VERSION 5.7 ;
  NOWIREEXTENSIONATPIN ON ;
  DIVIDERCHAR "/" ;
  BUSBITCHARS "[]" ;
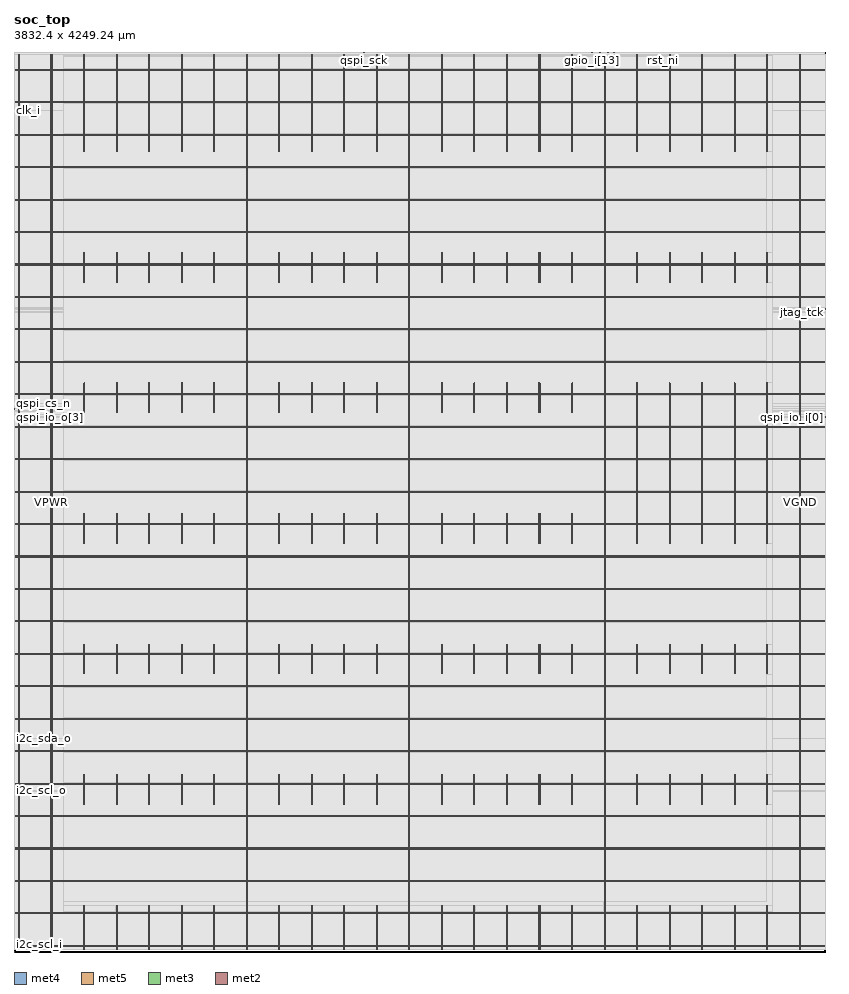
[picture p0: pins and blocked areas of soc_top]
MACRO soc_top
  CLASS BLOCK ;
  FOREIGN soc_top ;
  ORIGIN 0.000 0.000 ;
  SIZE 3832.400 BY 4249.240 ;
  PIN VGND
    DIRECTION INOUT ;
    USE GROUND ;
    PORT
      LAYER met4 ;
        RECT 24.340 10.640 25.940 4238.000 ;
    END
    PORT
      LAYER met4 ;
        RECT 177.940 10.640 179.540 4238.000 ;
    END
    PORT
      LAYER met4 ;
        RECT 331.540 10.640 333.140 220.320 ;
    END
    PORT
      LAYER met4 ;
        RECT 331.540 696.220 333.140 836.860 ;
    END
    PORT
      LAYER met4 ;
        RECT 331.540 1312.760 333.140 1453.400 ;
    END
    PORT
      LAYER met4 ;
        RECT 331.540 1929.300 333.140 2069.940 ;
    END
    PORT
      LAYER met4 ;
        RECT 331.540 2545.840 333.140 2686.480 ;
    END
    PORT
      LAYER met4 ;
        RECT 331.540 3162.380 333.140 3303.020 ;
    END
    PORT
      LAYER met4 ;
        RECT 331.540 3778.920 333.140 4238.000 ;
    END
    PORT
      LAYER met4 ;
        RECT 485.140 10.640 486.740 220.320 ;
    END
    PORT
      LAYER met4 ;
        RECT 485.140 696.220 486.740 836.860 ;
    END
    PORT
      LAYER met4 ;
        RECT 485.140 1312.760 486.740 1453.400 ;
    END
    PORT
      LAYER met4 ;
        RECT 485.140 1929.300 486.740 2069.940 ;
    END
    PORT
      LAYER met4 ;
        RECT 485.140 2545.840 486.740 2686.480 ;
    END
    PORT
      LAYER met4 ;
        RECT 485.140 3162.380 486.740 3303.020 ;
    END
    PORT
      LAYER met4 ;
        RECT 485.140 3778.920 486.740 4238.000 ;
    END
    PORT
      LAYER met4 ;
        RECT 638.740 10.640 640.340 220.320 ;
    END
    PORT
      LAYER met4 ;
        RECT 638.740 696.220 640.340 836.860 ;
    END
    PORT
      LAYER met4 ;
        RECT 638.740 1312.760 640.340 1453.400 ;
    END
    PORT
      LAYER met4 ;
        RECT 638.740 1929.300 640.340 2069.940 ;
    END
    PORT
      LAYER met4 ;
        RECT 638.740 2545.840 640.340 2686.480 ;
    END
    PORT
      LAYER met4 ;
        RECT 638.740 3162.380 640.340 3303.020 ;
    END
    PORT
      LAYER met4 ;
        RECT 638.740 3778.920 640.340 4238.000 ;
    END
    PORT
      LAYER met4 ;
        RECT 792.340 10.640 793.940 220.320 ;
    END
    PORT
      LAYER met4 ;
        RECT 792.340 696.220 793.940 836.860 ;
    END
    PORT
      LAYER met4 ;
        RECT 792.340 1312.760 793.940 1453.400 ;
    END
    PORT
      LAYER met4 ;
        RECT 792.340 1929.300 793.940 2069.940 ;
    END
    PORT
      LAYER met4 ;
        RECT 792.340 2545.840 793.940 2686.480 ;
    END
    PORT
      LAYER met4 ;
        RECT 792.340 3162.380 793.940 3303.020 ;
    END
    PORT
      LAYER met4 ;
        RECT 792.340 3778.920 793.940 4238.000 ;
    END
    PORT
      LAYER met4 ;
        RECT 945.940 10.640 947.540 220.320 ;
    END
    PORT
      LAYER met4 ;
        RECT 945.940 696.220 947.540 836.860 ;
    END
    PORT
      LAYER met4 ;
        RECT 945.940 1312.760 947.540 1453.400 ;
    END
    PORT
      LAYER met4 ;
        RECT 945.940 1929.300 947.540 2069.940 ;
    END
    PORT
      LAYER met4 ;
        RECT 945.940 2545.840 947.540 2686.480 ;
    END
    PORT
      LAYER met4 ;
        RECT 945.940 3162.380 947.540 3303.020 ;
    END
    PORT
      LAYER met4 ;
        RECT 945.940 3778.920 947.540 4238.000 ;
    END
    PORT
      LAYER met4 ;
        RECT 1099.540 10.640 1101.140 4238.000 ;
    END
    PORT
      LAYER met4 ;
        RECT 1253.140 10.640 1254.740 219.400 ;
    END
    PORT
      LAYER met4 ;
        RECT 1253.140 696.220 1254.740 835.940 ;
    END
    PORT
      LAYER met4 ;
        RECT 1253.140 1312.760 1254.740 1452.720 ;
    END
    PORT
      LAYER met4 ;
        RECT 1253.140 1929.300 1254.740 2069.020 ;
    END
    PORT
      LAYER met4 ;
        RECT 1253.140 2545.840 1254.740 2685.560 ;
    END
    PORT
      LAYER met4 ;
        RECT 1253.140 3162.380 1254.740 3302.320 ;
    END
    PORT
      LAYER met4 ;
        RECT 1253.140 3778.920 1254.740 4238.000 ;
    END
    PORT
      LAYER met4 ;
        RECT 1406.740 10.640 1408.340 220.320 ;
    END
    PORT
      LAYER met4 ;
        RECT 1406.740 696.220 1408.340 836.860 ;
    END
    PORT
      LAYER met4 ;
        RECT 1406.740 1312.760 1408.340 1453.400 ;
    END
    PORT
      LAYER met4 ;
        RECT 1406.740 1929.300 1408.340 2069.940 ;
    END
    PORT
      LAYER met4 ;
        RECT 1406.740 2545.840 1408.340 2686.480 ;
    END
    PORT
      LAYER met4 ;
        RECT 1406.740 3162.380 1408.340 3303.020 ;
    END
    PORT
      LAYER met4 ;
        RECT 1406.740 3778.920 1408.340 4238.000 ;
    END
    PORT
      LAYER met4 ;
        RECT 1560.340 10.640 1561.940 220.320 ;
    END
    PORT
      LAYER met4 ;
        RECT 1560.340 696.220 1561.940 836.860 ;
    END
    PORT
      LAYER met4 ;
        RECT 1560.340 1312.760 1561.940 1453.400 ;
    END
    PORT
      LAYER met4 ;
        RECT 1560.340 1929.300 1561.940 2069.940 ;
    END
    PORT
      LAYER met4 ;
        RECT 1560.340 2545.840 1561.940 2686.480 ;
    END
    PORT
      LAYER met4 ;
        RECT 1560.340 3162.380 1561.940 3303.020 ;
    END
    PORT
      LAYER met4 ;
        RECT 1560.340 3778.920 1561.940 4238.000 ;
    END
    PORT
      LAYER met4 ;
        RECT 1713.940 10.640 1715.540 220.320 ;
    END
    PORT
      LAYER met4 ;
        RECT 1713.940 696.220 1715.540 836.860 ;
    END
    PORT
      LAYER met4 ;
        RECT 1713.940 1312.760 1715.540 1453.400 ;
    END
    PORT
      LAYER met4 ;
        RECT 1713.940 1929.300 1715.540 2069.940 ;
    END
    PORT
      LAYER met4 ;
        RECT 1713.940 2545.840 1715.540 2686.480 ;
    END
    PORT
      LAYER met4 ;
        RECT 1713.940 3162.380 1715.540 3303.020 ;
    END
    PORT
      LAYER met4 ;
        RECT 1713.940 3778.920 1715.540 4238.000 ;
    END
    PORT
      LAYER met4 ;
        RECT 1867.540 10.640 1869.140 4238.000 ;
    END
    PORT
      LAYER met4 ;
        RECT 2021.140 10.640 2022.740 220.320 ;
    END
    PORT
      LAYER met4 ;
        RECT 2021.140 696.220 2022.740 836.860 ;
    END
    PORT
      LAYER met4 ;
        RECT 2021.140 1312.760 2022.740 1453.400 ;
    END
    PORT
      LAYER met4 ;
        RECT 2021.140 1929.300 2022.740 2069.940 ;
    END
    PORT
      LAYER met4 ;
        RECT 2021.140 2545.840 2022.740 2686.480 ;
    END
    PORT
      LAYER met4 ;
        RECT 2021.140 3162.380 2022.740 3303.020 ;
    END
    PORT
      LAYER met4 ;
        RECT 2021.140 3778.920 2022.740 4238.000 ;
    END
    PORT
      LAYER met4 ;
        RECT 2174.740 10.640 2176.340 220.320 ;
    END
    PORT
      LAYER met4 ;
        RECT 2174.740 696.220 2176.340 836.860 ;
    END
    PORT
      LAYER met4 ;
        RECT 2174.740 1312.760 2176.340 1453.400 ;
    END
    PORT
      LAYER met4 ;
        RECT 2174.740 1929.300 2176.340 2069.940 ;
    END
    PORT
      LAYER met4 ;
        RECT 2174.740 2545.840 2176.340 2686.480 ;
    END
    PORT
      LAYER met4 ;
        RECT 2174.740 3162.380 2176.340 3303.020 ;
    END
    PORT
      LAYER met4 ;
        RECT 2174.740 3778.920 2176.340 4238.000 ;
    END
    PORT
      LAYER met4 ;
        RECT 2328.340 10.640 2329.940 220.320 ;
    END
    PORT
      LAYER met4 ;
        RECT 2328.340 696.220 2329.940 836.860 ;
    END
    PORT
      LAYER met4 ;
        RECT 2328.340 1312.760 2329.940 1453.400 ;
    END
    PORT
      LAYER met4 ;
        RECT 2328.340 1929.300 2329.940 2069.940 ;
    END
    PORT
      LAYER met4 ;
        RECT 2328.340 2545.840 2329.940 2686.480 ;
    END
    PORT
      LAYER met4 ;
        RECT 2328.340 3162.380 2329.940 3303.020 ;
    END
    PORT
      LAYER met4 ;
        RECT 2328.340 3778.920 2329.940 4238.000 ;
    END
    PORT
      LAYER met4 ;
        RECT 2481.940 10.640 2483.540 219.400 ;
    END
    PORT
      LAYER met4 ;
        RECT 2481.940 697.140 2483.540 835.940 ;
    END
    PORT
      LAYER met4 ;
        RECT 2481.940 1313.680 2483.540 1452.720 ;
    END
    PORT
      LAYER met4 ;
        RECT 2481.940 1930.220 2483.540 2069.020 ;
    END
    PORT
      LAYER met4 ;
        RECT 2481.940 2546.760 2483.540 2685.560 ;
    END
    PORT
      LAYER met4 ;
        RECT 2481.940 3163.300 2483.540 3302.320 ;
    END
    PORT
      LAYER met4 ;
        RECT 2481.940 3779.840 2483.540 4238.000 ;
    END
    PORT
      LAYER met4 ;
        RECT 2635.540 10.640 2637.140 220.320 ;
    END
    PORT
      LAYER met4 ;
        RECT 2635.540 696.220 2637.140 836.860 ;
    END
    PORT
      LAYER met4 ;
        RECT 2635.540 1312.760 2637.140 1453.400 ;
    END
    PORT
      LAYER met4 ;
        RECT 2635.540 1929.300 2637.140 2069.940 ;
    END
    PORT
      LAYER met4 ;
        RECT 2635.540 2545.840 2637.140 2686.480 ;
    END
    PORT
      LAYER met4 ;
        RECT 2635.540 3162.380 2637.140 3303.020 ;
    END
    PORT
      LAYER met4 ;
        RECT 2635.540 3778.920 2637.140 4238.000 ;
    END
    PORT
      LAYER met4 ;
        RECT 2789.140 10.640 2790.740 4238.000 ;
    END
    PORT
      LAYER met4 ;
        RECT 2942.740 10.640 2944.340 220.320 ;
    END
    PORT
      LAYER met4 ;
        RECT 2942.740 696.220 2944.340 836.860 ;
    END
    PORT
      LAYER met4 ;
        RECT 2942.740 1312.760 2944.340 1453.400 ;
    END
    PORT
      LAYER met4 ;
        RECT 2942.740 1929.300 2944.340 2686.480 ;
    END
    PORT
      LAYER met4 ;
        RECT 2942.740 3162.380 2944.340 3303.020 ;
    END
    PORT
      LAYER met4 ;
        RECT 2942.740 3778.920 2944.340 4238.000 ;
    END
    PORT
      LAYER met4 ;
        RECT 3096.340 10.640 3097.940 219.400 ;
    END
    PORT
      LAYER met4 ;
        RECT 3096.340 696.220 3097.940 835.940 ;
    END
    PORT
      LAYER met4 ;
        RECT 3096.340 1312.760 3097.940 1452.720 ;
    END
    PORT
      LAYER met4 ;
        RECT 3096.340 1929.300 3097.940 2685.560 ;
    END
    PORT
      LAYER met4 ;
        RECT 3096.340 3162.380 3097.940 3302.320 ;
    END
    PORT
      LAYER met4 ;
        RECT 3096.340 3778.920 3097.940 4238.000 ;
    END
    PORT
      LAYER met4 ;
        RECT 3249.940 10.640 3251.540 220.320 ;
    END
    PORT
      LAYER met4 ;
        RECT 3249.940 696.220 3251.540 836.860 ;
    END
    PORT
      LAYER met4 ;
        RECT 3249.940 1312.760 3251.540 1453.400 ;
    END
    PORT
      LAYER met4 ;
        RECT 3249.940 1929.300 3251.540 2686.480 ;
    END
    PORT
      LAYER met4 ;
        RECT 3249.940 3162.380 3251.540 3303.020 ;
    END
    PORT
      LAYER met4 ;
        RECT 3249.940 3778.920 3251.540 4238.000 ;
    END
    PORT
      LAYER met4 ;
        RECT 3403.540 10.640 3405.140 219.400 ;
    END
    PORT
      LAYER met4 ;
        RECT 3403.540 697.140 3405.140 835.940 ;
    END
    PORT
      LAYER met4 ;
        RECT 3403.540 1313.680 3405.140 1452.720 ;
    END
    PORT
      LAYER met4 ;
        RECT 3403.540 1930.220 3405.140 2685.560 ;
    END
    PORT
      LAYER met4 ;
        RECT 3403.540 3163.300 3405.140 3302.320 ;
    END
    PORT
      LAYER met4 ;
        RECT 3403.540 3779.840 3405.140 4238.000 ;
    END
    PORT
      LAYER met4 ;
        RECT 3557.140 10.640 3558.740 220.320 ;
    END
    PORT
      LAYER met4 ;
        RECT 3557.140 696.220 3558.740 836.860 ;
    END
    PORT
      LAYER met4 ;
        RECT 3557.140 1312.760 3558.740 1453.400 ;
    END
    PORT
      LAYER met4 ;
        RECT 3557.140 1929.300 3558.740 2686.480 ;
    END
    PORT
      LAYER met4 ;
        RECT 3557.140 3162.380 3558.740 3303.020 ;
    END
    PORT
      LAYER met4 ;
        RECT 3557.140 3778.920 3558.740 4238.000 ;
    END
    PORT
      LAYER met4 ;
        RECT 3710.740 10.640 3712.340 4238.000 ;
    END
    PORT
      LAYER met5 ;
        RECT 5.520 30.030 3826.740 31.630 ;
    END
    PORT
      LAYER met5 ;
        RECT 5.520 183.210 3826.740 184.810 ;
    END
    PORT
      LAYER met5 ;
        RECT 5.520 336.390 3826.740 337.990 ;
    END
    PORT
      LAYER met5 ;
        RECT 5.520 489.570 3826.740 491.170 ;
    END
    PORT
      LAYER met5 ;
        RECT 5.520 642.750 3826.740 644.350 ;
    END
    PORT
      LAYER met5 ;
        RECT 5.520 795.930 3826.740 797.530 ;
    END
    PORT
      LAYER met5 ;
        RECT 5.520 949.110 3826.740 950.710 ;
    END
    PORT
      LAYER met5 ;
        RECT 5.520 1102.290 3826.740 1103.890 ;
    END
    PORT
      LAYER met5 ;
        RECT 5.520 1255.470 3826.740 1257.070 ;
    END
    PORT
      LAYER met5 ;
        RECT 5.520 1408.650 3826.740 1410.250 ;
    END
    PORT
      LAYER met5 ;
        RECT 5.520 1561.830 3826.740 1563.430 ;
    END
    PORT
      LAYER met5 ;
        RECT 5.520 1715.010 3826.740 1716.610 ;
    END
    PORT
      LAYER met5 ;
        RECT 5.520 1868.190 3826.740 1869.790 ;
    END
    PORT
      LAYER met5 ;
        RECT 5.520 2021.370 3826.740 2022.970 ;
    END
    PORT
      LAYER met5 ;
        RECT 5.520 2174.550 3826.740 2176.150 ;
    END
    PORT
      LAYER met5 ;
        RECT 5.520 2327.730 3826.740 2329.330 ;
    END
    PORT
      LAYER met5 ;
        RECT 5.520 2480.910 3826.740 2482.510 ;
    END
    PORT
      LAYER met5 ;
        RECT 5.520 2634.090 3826.740 2635.690 ;
    END
    PORT
      LAYER met5 ;
        RECT 5.520 2787.270 3826.740 2788.870 ;
    END
    PORT
      LAYER met5 ;
        RECT 5.520 2940.450 3826.740 2942.050 ;
    END
    PORT
      LAYER met5 ;
        RECT 5.520 3093.630 3826.740 3095.230 ;
    END
    PORT
      LAYER met5 ;
        RECT 5.520 3246.810 3826.740 3248.410 ;
    END
    PORT
      LAYER met5 ;
        RECT 5.520 3399.990 3826.740 3401.590 ;
    END
    PORT
      LAYER met5 ;
        RECT 5.520 3553.170 3826.740 3554.770 ;
    END
    PORT
      LAYER met5 ;
        RECT 5.520 3706.350 3826.740 3707.950 ;
    END
    PORT
      LAYER met5 ;
        RECT 5.520 3859.530 3826.740 3861.130 ;
    END
    PORT
      LAYER met5 ;
        RECT 5.520 4012.710 3826.740 4014.310 ;
    END
    PORT
      LAYER met5 ;
        RECT 5.520 4165.890 3826.740 4167.490 ;
    END
  END VGND
  PIN VPWR
    DIRECTION INOUT ;
    USE POWER ;
    PORT
      LAYER met4 ;
        RECT 21.040 10.640 22.640 4238.000 ;
    END
    PORT
      LAYER met4 ;
        RECT 174.640 10.640 176.240 4238.000 ;
    END
    PORT
      LAYER met4 ;
        RECT 328.240 10.640 329.840 219.400 ;
    END
    PORT
      LAYER met4 ;
        RECT 328.240 696.220 329.840 835.940 ;
    END
    PORT
      LAYER met4 ;
        RECT 328.240 1312.760 329.840 1452.480 ;
    END
    PORT
      LAYER met4 ;
        RECT 328.240 1929.300 329.840 2069.020 ;
    END
    PORT
      LAYER met4 ;
        RECT 328.240 2545.840 329.840 2685.560 ;
    END
    PORT
      LAYER met4 ;
        RECT 328.240 3162.380 329.840 3302.100 ;
    END
    PORT
      LAYER met4 ;
        RECT 328.240 3778.920 329.840 4238.000 ;
    END
    PORT
      LAYER met4 ;
        RECT 481.840 10.640 483.440 219.400 ;
    END
    PORT
      LAYER met4 ;
        RECT 481.840 696.220 483.440 835.940 ;
    END
    PORT
      LAYER met4 ;
        RECT 481.840 1312.760 483.440 1452.480 ;
    END
    PORT
      LAYER met4 ;
        RECT 481.840 1929.300 483.440 2069.020 ;
    END
    PORT
      LAYER met4 ;
        RECT 481.840 2545.840 483.440 2685.560 ;
    END
    PORT
      LAYER met4 ;
        RECT 481.840 3162.380 483.440 3302.100 ;
    END
    PORT
      LAYER met4 ;
        RECT 481.840 3778.920 483.440 4238.000 ;
    END
    PORT
      LAYER met4 ;
        RECT 635.440 10.640 637.040 220.320 ;
    END
    PORT
      LAYER met4 ;
        RECT 635.440 696.220 637.040 836.860 ;
    END
    PORT
      LAYER met4 ;
        RECT 635.440 1312.760 637.040 1453.400 ;
    END
    PORT
      LAYER met4 ;
        RECT 635.440 1929.300 637.040 2069.940 ;
    END
    PORT
      LAYER met4 ;
        RECT 635.440 2545.840 637.040 2686.480 ;
    END
    PORT
      LAYER met4 ;
        RECT 635.440 3162.380 637.040 3303.020 ;
    END
    PORT
      LAYER met4 ;
        RECT 635.440 3778.920 637.040 4238.000 ;
    END
    PORT
      LAYER met4 ;
        RECT 789.040 10.640 790.640 220.320 ;
    END
    PORT
      LAYER met4 ;
        RECT 789.040 696.220 790.640 836.860 ;
    END
    PORT
      LAYER met4 ;
        RECT 789.040 1312.760 790.640 1453.400 ;
    END
    PORT
      LAYER met4 ;
        RECT 789.040 1929.300 790.640 2069.940 ;
    END
    PORT
      LAYER met4 ;
        RECT 789.040 2545.840 790.640 2686.480 ;
    END
    PORT
      LAYER met4 ;
        RECT 789.040 3162.380 790.640 3303.020 ;
    END
    PORT
      LAYER met4 ;
        RECT 789.040 3778.920 790.640 4238.000 ;
    END
    PORT
      LAYER met4 ;
        RECT 942.640 10.640 944.240 220.320 ;
    END
    PORT
      LAYER met4 ;
        RECT 942.640 696.220 944.240 836.860 ;
    END
    PORT
      LAYER met4 ;
        RECT 942.640 1312.760 944.240 1453.400 ;
    END
    PORT
      LAYER met4 ;
        RECT 942.640 1929.300 944.240 2069.940 ;
    END
    PORT
      LAYER met4 ;
        RECT 942.640 2545.840 944.240 2686.480 ;
    END
    PORT
      LAYER met4 ;
        RECT 942.640 3162.380 944.240 3303.020 ;
    END
    PORT
      LAYER met4 ;
        RECT 942.640 3778.920 944.240 4238.000 ;
    END
    PORT
      LAYER met4 ;
        RECT 1096.240 10.640 1097.840 4238.000 ;
    END
    PORT
      LAYER met4 ;
        RECT 1249.840 10.640 1251.440 220.320 ;
    END
    PORT
      LAYER met4 ;
        RECT 1249.840 696.220 1251.440 836.860 ;
    END
    PORT
      LAYER met4 ;
        RECT 1249.840 1312.760 1251.440 1453.400 ;
    END
    PORT
      LAYER met4 ;
        RECT 1249.840 1929.300 1251.440 2069.940 ;
    END
    PORT
      LAYER met4 ;
        RECT 1249.840 2545.840 1251.440 2686.480 ;
    END
    PORT
      LAYER met4 ;
        RECT 1249.840 3162.380 1251.440 3303.020 ;
    END
    PORT
      LAYER met4 ;
        RECT 1249.840 3778.920 1251.440 4238.000 ;
    END
    PORT
      LAYER met4 ;
        RECT 1403.440 10.640 1405.040 219.400 ;
    END
    PORT
      LAYER met4 ;
        RECT 1403.440 696.220 1405.040 835.940 ;
    END
    PORT
      LAYER met4 ;
        RECT 1403.440 1312.760 1405.040 1452.480 ;
    END
    PORT
      LAYER met4 ;
        RECT 1403.440 1929.300 1405.040 2069.020 ;
    END
    PORT
      LAYER met4 ;
        RECT 1403.440 2545.840 1405.040 2685.560 ;
    END
    PORT
      LAYER met4 ;
        RECT 1403.440 3162.380 1405.040 3302.100 ;
    END
    PORT
      LAYER met4 ;
        RECT 1403.440 3778.920 1405.040 4238.000 ;
    END
    PORT
      LAYER met4 ;
        RECT 1557.040 10.640 1558.640 220.320 ;
    END
    PORT
      LAYER met4 ;
        RECT 1557.040 696.220 1558.640 836.860 ;
    END
    PORT
      LAYER met4 ;
        RECT 1557.040 1312.760 1558.640 1453.400 ;
    END
    PORT
      LAYER met4 ;
        RECT 1557.040 1929.300 1558.640 2069.940 ;
    END
    PORT
      LAYER met4 ;
        RECT 1557.040 2545.840 1558.640 2686.480 ;
    END
    PORT
      LAYER met4 ;
        RECT 1557.040 3162.380 1558.640 3303.020 ;
    END
    PORT
      LAYER met4 ;
        RECT 1557.040 3778.920 1558.640 4238.000 ;
    END
    PORT
      LAYER met4 ;
        RECT 1710.640 10.640 1712.240 220.320 ;
    END
    PORT
      LAYER met4 ;
        RECT 1710.640 696.220 1712.240 836.860 ;
    END
    PORT
      LAYER met4 ;
        RECT 1710.640 1312.760 1712.240 1453.400 ;
    END
    PORT
      LAYER met4 ;
        RECT 1710.640 1929.300 1712.240 2069.940 ;
    END
    PORT
      LAYER met4 ;
        RECT 1710.640 2545.840 1712.240 2686.480 ;
    END
    PORT
      LAYER met4 ;
        RECT 1710.640 3162.380 1712.240 3303.020 ;
    END
    PORT
      LAYER met4 ;
        RECT 1710.640 3778.920 1712.240 4238.000 ;
    END
    PORT
      LAYER met4 ;
        RECT 1864.240 10.640 1865.840 4238.000 ;
    END
    PORT
      LAYER met4 ;
        RECT 2017.840 10.640 2019.440 220.320 ;
    END
    PORT
      LAYER met4 ;
        RECT 2017.840 696.220 2019.440 836.860 ;
    END
    PORT
      LAYER met4 ;
        RECT 2017.840 1312.760 2019.440 1453.400 ;
    END
    PORT
      LAYER met4 ;
        RECT 2017.840 1929.300 2019.440 2069.940 ;
    END
    PORT
      LAYER met4 ;
        RECT 2017.840 2545.840 2019.440 2686.480 ;
    END
    PORT
      LAYER met4 ;
        RECT 2017.840 3162.380 2019.440 3303.020 ;
    END
    PORT
      LAYER met4 ;
        RECT 2017.840 3778.920 2019.440 4238.000 ;
    END
    PORT
      LAYER met4 ;
        RECT 2171.440 10.640 2173.040 219.400 ;
    END
    PORT
      LAYER met4 ;
        RECT 2171.440 697.140 2173.040 835.940 ;
    END
    PORT
      LAYER met4 ;
        RECT 2171.440 1313.520 2173.040 1452.480 ;
    END
    PORT
      LAYER met4 ;
        RECT 2171.440 1930.220 2173.040 2069.020 ;
    END
    PORT
      LAYER met4 ;
        RECT 2171.440 2546.760 2173.040 2685.560 ;
    END
    PORT
      LAYER met4 ;
        RECT 2171.440 3163.120 2173.040 3302.100 ;
    END
    PORT
      LAYER met4 ;
        RECT 2171.440 3779.840 2173.040 4238.000 ;
    END
    PORT
      LAYER met4 ;
        RECT 2325.040 10.640 2326.640 220.320 ;
    END
    PORT
      LAYER met4 ;
        RECT 2325.040 696.220 2326.640 836.860 ;
    END
    PORT
      LAYER met4 ;
        RECT 2325.040 1312.760 2326.640 1453.400 ;
    END
    PORT
      LAYER met4 ;
        RECT 2325.040 1929.300 2326.640 2069.940 ;
    END
    PORT
      LAYER met4 ;
        RECT 2325.040 2545.840 2326.640 2686.480 ;
    END
    PORT
      LAYER met4 ;
        RECT 2325.040 3162.380 2326.640 3303.020 ;
    END
    PORT
      LAYER met4 ;
        RECT 2325.040 3778.920 2326.640 4238.000 ;
    END
    PORT
      LAYER met4 ;
        RECT 2478.640 10.640 2480.240 220.320 ;
    END
    PORT
      LAYER met4 ;
        RECT 2478.640 696.220 2480.240 836.860 ;
    END
    PORT
      LAYER met4 ;
        RECT 2478.640 1312.760 2480.240 1453.400 ;
    END
    PORT
      LAYER met4 ;
        RECT 2478.640 1929.300 2480.240 2069.940 ;
    END
    PORT
      LAYER met4 ;
        RECT 2478.640 2545.840 2480.240 2686.480 ;
    END
    PORT
      LAYER met4 ;
        RECT 2478.640 3162.380 2480.240 3303.020 ;
    END
    PORT
      LAYER met4 ;
        RECT 2478.640 3778.920 2480.240 4238.000 ;
    END
    PORT
      LAYER met4 ;
        RECT 2632.240 10.640 2633.840 219.400 ;
    END
    PORT
      LAYER met4 ;
        RECT 2632.240 696.220 2633.840 835.940 ;
    END
    PORT
      LAYER met4 ;
        RECT 2632.240 1312.760 2633.840 1452.480 ;
    END
    PORT
      LAYER met4 ;
        RECT 2632.240 1929.300 2633.840 2069.020 ;
    END
    PORT
      LAYER met4 ;
        RECT 2632.240 2545.840 2633.840 2685.560 ;
    END
    PORT
      LAYER met4 ;
        RECT 2632.240 3162.380 2633.840 3302.100 ;
    END
    PORT
      LAYER met4 ;
        RECT 2632.240 3778.920 2633.840 4238.000 ;
    END
    PORT
      LAYER met4 ;
        RECT 2785.840 10.640 2787.440 4238.000 ;
    END
    PORT
      LAYER met4 ;
        RECT 2939.440 10.640 2941.040 220.320 ;
    END
    PORT
      LAYER met4 ;
        RECT 2939.440 696.220 2941.040 836.860 ;
    END
    PORT
      LAYER met4 ;
        RECT 2939.440 1312.760 2941.040 1453.400 ;
    END
    PORT
      LAYER met4 ;
        RECT 2939.440 1929.300 2941.040 2686.480 ;
    END
    PORT
      LAYER met4 ;
        RECT 2939.440 3162.380 2941.040 3303.020 ;
    END
    PORT
      LAYER met4 ;
        RECT 2939.440 3778.920 2941.040 4238.000 ;
    END
    PORT
      LAYER met4 ;
        RECT 3093.040 10.640 3094.640 220.320 ;
    END
    PORT
      LAYER met4 ;
        RECT 3093.040 696.220 3094.640 836.860 ;
    END
    PORT
      LAYER met4 ;
        RECT 3093.040 1312.760 3094.640 1453.400 ;
    END
    PORT
      LAYER met4 ;
        RECT 3093.040 1929.300 3094.640 2686.480 ;
    END
    PORT
      LAYER met4 ;
        RECT 3093.040 3162.380 3094.640 3303.020 ;
    END
    PORT
      LAYER met4 ;
        RECT 3093.040 3778.920 3094.640 4238.000 ;
    END
    PORT
      LAYER met4 ;
        RECT 3246.640 10.640 3248.240 220.320 ;
    END
    PORT
      LAYER met4 ;
        RECT 3246.640 696.220 3248.240 836.860 ;
    END
    PORT
      LAYER met4 ;
        RECT 3246.640 1312.760 3248.240 1453.400 ;
    END
    PORT
      LAYER met4 ;
        RECT 3246.640 1929.300 3248.240 2686.480 ;
    END
    PORT
      LAYER met4 ;
        RECT 3246.640 3162.380 3248.240 3303.020 ;
    END
    PORT
      LAYER met4 ;
        RECT 3246.640 3778.920 3248.240 4238.000 ;
    END
    PORT
      LAYER met4 ;
        RECT 3400.240 10.640 3401.840 220.320 ;
    END
    PORT
      LAYER met4 ;
        RECT 3400.240 696.220 3401.840 836.860 ;
    END
    PORT
      LAYER met4 ;
        RECT 3400.240 1312.760 3401.840 1453.400 ;
    END
    PORT
      LAYER met4 ;
        RECT 3400.240 1929.300 3401.840 2686.480 ;
    END
    PORT
      LAYER met4 ;
        RECT 3400.240 3162.380 3401.840 3303.020 ;
    END
    PORT
      LAYER met4 ;
        RECT 3400.240 3778.920 3401.840 4238.000 ;
    END
    PORT
      LAYER met4 ;
        RECT 3553.840 10.640 3555.440 220.320 ;
    END
    PORT
      LAYER met4 ;
        RECT 3553.840 697.140 3555.440 836.860 ;
    END
    PORT
      LAYER met4 ;
        RECT 3553.840 1313.520 3555.440 1453.400 ;
    END
    PORT
      LAYER met4 ;
        RECT 3553.840 1930.220 3555.440 2686.480 ;
    END
    PORT
      LAYER met4 ;
        RECT 3553.840 3163.120 3555.440 3303.020 ;
    END
    PORT
      LAYER met4 ;
        RECT 3553.840 3779.840 3555.440 4238.000 ;
    END
    PORT
      LAYER met4 ;
        RECT 3707.440 10.640 3709.040 4238.000 ;
    END
    PORT
      LAYER met5 ;
        RECT 5.520 26.730 3826.740 28.330 ;
    END
    PORT
      LAYER met5 ;
        RECT 5.520 179.910 3826.740 181.510 ;
    END
    PORT
      LAYER met5 ;
        RECT 5.520 333.090 3826.740 334.690 ;
    END
    PORT
      LAYER met5 ;
        RECT 5.520 486.270 3826.740 487.870 ;
    END
    PORT
      LAYER met5 ;
        RECT 5.520 639.450 3826.740 641.050 ;
    END
    PORT
      LAYER met5 ;
        RECT 5.520 792.630 3826.740 794.230 ;
    END
    PORT
      LAYER met5 ;
        RECT 5.520 945.810 3826.740 947.410 ;
    END
    PORT
      LAYER met5 ;
        RECT 5.520 1098.990 3826.740 1100.590 ;
    END
    PORT
      LAYER met5 ;
        RECT 5.520 1252.170 3826.740 1253.770 ;
    END
    PORT
      LAYER met5 ;
        RECT 5.520 1405.350 3826.740 1406.950 ;
    END
    PORT
      LAYER met5 ;
        RECT 5.520 1558.530 3826.740 1560.130 ;
    END
    PORT
      LAYER met5 ;
        RECT 5.520 1711.710 3826.740 1713.310 ;
    END
    PORT
      LAYER met5 ;
        RECT 5.520 1864.890 3826.740 1866.490 ;
    END
    PORT
      LAYER met5 ;
        RECT 5.520 2018.070 3826.740 2019.670 ;
    END
    PORT
      LAYER met5 ;
        RECT 5.520 2171.250 3826.740 2172.850 ;
    END
    PORT
      LAYER met5 ;
        RECT 5.520 2324.430 3826.740 2326.030 ;
    END
    PORT
      LAYER met5 ;
        RECT 5.520 2477.610 3826.740 2479.210 ;
    END
    PORT
      LAYER met5 ;
        RECT 5.520 2630.790 3826.740 2632.390 ;
    END
    PORT
      LAYER met5 ;
        RECT 5.520 2783.970 3826.740 2785.570 ;
    END
    PORT
      LAYER met5 ;
        RECT 5.520 2937.150 3826.740 2938.750 ;
    END
    PORT
      LAYER met5 ;
        RECT 5.520 3090.330 3826.740 3091.930 ;
    END
    PORT
      LAYER met5 ;
        RECT 5.520 3243.510 3826.740 3245.110 ;
    END
    PORT
      LAYER met5 ;
        RECT 5.520 3396.690 3826.740 3398.290 ;
    END
    PORT
      LAYER met5 ;
        RECT 5.520 3549.870 3826.740 3551.470 ;
    END
    PORT
      LAYER met5 ;
        RECT 5.520 3703.050 3826.740 3704.650 ;
    END
    PORT
      LAYER met5 ;
        RECT 5.520 3856.230 3826.740 3857.830 ;
    END
    PORT
      LAYER met5 ;
        RECT 5.520 4009.410 3826.740 4011.010 ;
    END
    PORT
      LAYER met5 ;
        RECT 5.520 4162.590 3826.740 4164.190 ;
    END
  END VPWR
  PIN clk_i
    DIRECTION INPUT ;
    USE SIGNAL ;
    ANTENNAGATEAREA 2.138700 ;
    ANTENNADIFFAREA 0.434700 ;
    PORT
      LAYER met3 ;
        RECT 0.000 3973.960 0.600 3974.560 ;
    END
  END clk_i
  PIN gpio_i[0]
    DIRECTION INPUT ;
    USE SIGNAL ;
    ANTENNAGATEAREA 0.213000 ;
    PORT
      LAYER met2 ;
        RECT 2809.770 4248.960 2810.050 4249.240 ;
    END
  END gpio_i[0]
  PIN gpio_i[10]
    DIRECTION INPUT ;
    USE SIGNAL ;
    ANTENNAGATEAREA 0.213000 ;
    PORT
      LAYER met2 ;
        RECT 2767.450 4248.960 2767.730 4249.240 ;
    END
  END gpio_i[10]
  PIN gpio_i[11]
    DIRECTION INPUT ;
    USE SIGNAL ;
    ANTENNAGATEAREA 0.213000 ;
    PORT
      LAYER met2 ;
        RECT 2729.730 4248.960 2730.010 4249.240 ;
    END
  END gpio_i[11]
  PIN gpio_i[12]
    DIRECTION INPUT ;
    USE SIGNAL ;
    ANTENNAGATEAREA 0.213000 ;
    PORT
      LAYER met2 ;
        RECT 2786.770 4248.960 2787.050 4249.240 ;
    END
  END gpio_i[12]
  PIN gpio_i[13]
    DIRECTION INPUT ;
    USE SIGNAL ;
    ANTENNAGATEAREA 0.213000 ;
    PORT
      LAYER met2 ;
        RECT 2730.650 4248.960 2730.930 4249.240 ;
    END
  END gpio_i[13]
  PIN gpio_i[14]
    DIRECTION INPUT ;
    USE SIGNAL ;
    ANTENNAGATEAREA 0.213000 ;
    PORT
      LAYER met2 ;
        RECT 2833.690 4248.960 2833.970 4249.240 ;
    END
  END gpio_i[14]
  PIN gpio_i[15]
    DIRECTION INPUT ;
    USE SIGNAL ;
    ANTENNAGATEAREA 0.213000 ;
    PORT
      LAYER met2 ;
        RECT 2841.970 4248.960 2842.250 4249.240 ;
    END
  END gpio_i[15]
  PIN gpio_i[1]
    DIRECTION INPUT ;
    USE SIGNAL ;
    ANTENNAGATEAREA 0.213000 ;
    PORT
      LAYER met2 ;
        RECT 2769.290 4248.960 2769.570 4249.240 ;
    END
  END gpio_i[1]
  PIN gpio_i[2]
    DIRECTION INPUT ;
    USE SIGNAL ;
    ANTENNAGATEAREA 0.213000 ;
    PORT
      LAYER met2 ;
        RECT 2726.970 4248.960 2727.250 4249.240 ;
    END
  END gpio_i[2]
  PIN gpio_i[3]
    DIRECTION INPUT ;
    USE SIGNAL ;
    ANTENNAGATEAREA 0.213000 ;
    PORT
      LAYER met2 ;
        RECT 2727.890 4248.960 2728.170 4249.240 ;
    END
  END gpio_i[3]
  PIN gpio_i[4]
    DIRECTION INPUT ;
    USE SIGNAL ;
    ANTENNAGATEAREA 0.213000 ;
    PORT
      LAYER met2 ;
        RECT 2728.810 4248.960 2729.090 4249.240 ;
    END
  END gpio_i[4]
  PIN gpio_i[5]
    DIRECTION INPUT ;
    USE SIGNAL ;
    ANTENNAGATEAREA 0.213000 ;
    PORT
      LAYER met2 ;
        RECT 2820.810 4248.960 2821.090 4249.240 ;
    END
  END gpio_i[5]
  PIN gpio_i[6]
    DIRECTION INPUT ;
    USE SIGNAL ;
    ANTENNAGATEAREA 0.213000 ;
    PORT
      LAYER met2 ;
        RECT 2832.770 4248.960 2833.050 4249.240 ;
    END
  END gpio_i[6]
  PIN gpio_i[7]
    DIRECTION INPUT ;
    USE SIGNAL ;
    ANTENNAGATEAREA 0.213000 ;
    PORT
      LAYER met2 ;
        RECT 2842.890 4248.960 2843.170 4249.240 ;
    END
  END gpio_i[7]
  PIN gpio_i[8]
    DIRECTION INPUT ;
    USE SIGNAL ;
    ANTENNAGATEAREA 0.213000 ;
    PORT
      LAYER met2 ;
        RECT 2828.170 4248.960 2828.450 4249.240 ;
    END
  END gpio_i[8]
  PIN gpio_i[9]
    DIRECTION INPUT ;
    USE SIGNAL ;
    ANTENNAGATEAREA 0.213000 ;
    PORT
      LAYER met2 ;
        RECT 2738.930 4248.960 2739.210 4249.240 ;
    END
  END gpio_i[9]
  PIN gpio_o[0]
    DIRECTION OUTPUT ;
    USE SIGNAL ;
    ANTENNADIFFAREA 0.702900 ;
    PORT
      LAYER met2 ;
        RECT 2802.410 4248.960 2802.690 4249.240 ;
    END
  END gpio_o[0]
  PIN gpio_o[10]
    DIRECTION OUTPUT ;
    USE SIGNAL ;
    ANTENNADIFFAREA 0.702900 ;
    PORT
      LAYER met2 ;
        RECT 2781.250 4248.960 2781.530 4249.240 ;
    END
  END gpio_o[10]
  PIN gpio_o[11]
    DIRECTION OUTPUT ;
    USE SIGNAL ;
    ANTENNADIFFAREA 0.702900 ;
    PORT
      LAYER met2 ;
        RECT 2741.690 4248.960 2741.970 4249.240 ;
    END
  END gpio_o[11]
  PIN gpio_o[12]
    DIRECTION OUTPUT ;
    USE SIGNAL ;
    ANTENNADIFFAREA 0.702900 ;
    PORT
      LAYER met2 ;
        RECT 2777.570 4248.960 2777.850 4249.240 ;
    END
  END gpio_o[12]
  PIN gpio_o[13]
    DIRECTION OUTPUT ;
    USE SIGNAL ;
    ANTENNADIFFAREA 0.702900 ;
    PORT
      LAYER met2 ;
        RECT 2745.370 4248.960 2745.650 4249.240 ;
    END
  END gpio_o[13]
  PIN gpio_o[14]
    DIRECTION OUTPUT ;
    USE SIGNAL ;
    ANTENNADIFFAREA 0.702900 ;
    PORT
      LAYER met2 ;
        RECT 2808.850 4248.960 2809.130 4249.240 ;
    END
  END gpio_o[14]
  PIN gpio_o[15]
    DIRECTION OUTPUT ;
    USE SIGNAL ;
    ANTENNADIFFAREA 0.702900 ;
    PORT
      LAYER met2 ;
        RECT 2807.930 4248.960 2808.210 4249.240 ;
    END
  END gpio_o[15]
  PIN gpio_o[1]
    DIRECTION OUTPUT ;
    USE SIGNAL ;
    ANTENNADIFFAREA 0.702900 ;
    PORT
      LAYER met2 ;
        RECT 2784.010 4248.960 2784.290 4249.240 ;
    END
  END gpio_o[1]
  PIN gpio_o[2]
    DIRECTION OUTPUT ;
    USE SIGNAL ;
    ANTENNADIFFAREA 0.702900 ;
    PORT
      LAYER met2 ;
        RECT 2783.090 4248.960 2783.370 4249.240 ;
    END
  END gpio_o[2]
  PIN gpio_o[3]
    DIRECTION OUTPUT ;
    USE SIGNAL ;
    ANTENNADIFFAREA 0.702900 ;
    PORT
      LAYER met2 ;
        RECT 2806.090 4248.960 2806.370 4249.240 ;
    END
  END gpio_o[3]
  PIN gpio_o[4]
    DIRECTION OUTPUT ;
    USE SIGNAL ;
    ANTENNADIFFAREA 0.702900 ;
    PORT
      LAYER met2 ;
        RECT 2768.370 4248.960 2768.650 4249.240 ;
    END
  END gpio_o[4]
  PIN gpio_o[5]
    DIRECTION OUTPUT ;
    USE SIGNAL ;
    ANTENNADIFFAREA 0.702900 ;
    PORT
      LAYER met2 ;
        RECT 2782.170 4248.960 2782.450 4249.240 ;
    END
  END gpio_o[5]
  PIN gpio_o[6]
    DIRECTION OUTPUT ;
    USE SIGNAL ;
    ANTENNADIFFAREA 0.702900 ;
    PORT
      LAYER met2 ;
        RECT 2803.330 4248.960 2803.610 4249.240 ;
    END
  END gpio_o[6]
  PIN gpio_o[7]
    DIRECTION OUTPUT ;
    USE SIGNAL ;
    ANTENNADIFFAREA 0.702900 ;
    PORT
      LAYER met2 ;
        RECT 2805.170 4248.960 2805.450 4249.240 ;
    END
  END gpio_o[7]
  PIN gpio_o[8]
    DIRECTION OUTPUT ;
    USE SIGNAL ;
    ANTENNADIFFAREA 0.702900 ;
    PORT
      LAYER met2 ;
        RECT 2804.250 4248.960 2804.530 4249.240 ;
    END
  END gpio_o[8]
  PIN gpio_o[9]
    DIRECTION OUTPUT ;
    USE SIGNAL ;
    ANTENNADIFFAREA 0.702900 ;
    PORT
      LAYER met2 ;
        RECT 2751.810 4248.960 2752.090 4249.240 ;
    END
  END gpio_o[9]
  PIN gpio_tx_en_o[0]
    DIRECTION OUTPUT ;
    USE SIGNAL ;
    ANTENNADIFFAREA 0.702900 ;
    PORT
      LAYER met2 ;
        RECT 2797.810 4248.960 2798.090 4249.240 ;
    END
  END gpio_tx_en_o[0]
  PIN gpio_tx_en_o[10]
    DIRECTION OUTPUT ;
    USE SIGNAL ;
    ANTENNADIFFAREA 0.702900 ;
    PORT
      LAYER met2 ;
        RECT 2747.210 4248.960 2747.490 4249.240 ;
    END
  END gpio_tx_en_o[10]
  PIN gpio_tx_en_o[11]
    DIRECTION OUTPUT ;
    USE SIGNAL ;
    ANTENNADIFFAREA 0.702900 ;
    PORT
      LAYER met2 ;
        RECT 2740.770 4248.960 2741.050 4249.240 ;
    END
  END gpio_tx_en_o[11]
  PIN gpio_tx_en_o[12]
    DIRECTION OUTPUT ;
    USE SIGNAL ;
    ANTENNADIFFAREA 0.702900 ;
    PORT
      LAYER met2 ;
        RECT 2752.730 4248.960 2753.010 4249.240 ;
    END
  END gpio_tx_en_o[12]
  PIN gpio_tx_en_o[13]
    DIRECTION OUTPUT ;
    USE SIGNAL ;
    ANTENNADIFFAREA 0.702900 ;
    PORT
      LAYER met2 ;
        RECT 2748.130 4248.960 2748.410 4249.240 ;
    END
  END gpio_tx_en_o[13]
  PIN gpio_tx_en_o[14]
    DIRECTION OUTPUT ;
    USE SIGNAL ;
    ANTENNADIFFAREA 0.702900 ;
    PORT
      LAYER met2 ;
        RECT 2742.610 4248.960 2742.890 4249.240 ;
    END
  END gpio_tx_en_o[14]
  PIN gpio_tx_en_o[15]
    DIRECTION OUTPUT ;
    USE SIGNAL ;
    ANTENNADIFFAREA 0.702900 ;
    PORT
      LAYER met2 ;
        RECT 2758.250 4248.960 2758.530 4249.240 ;
    END
  END gpio_tx_en_o[15]
  PIN gpio_tx_en_o[1]
    DIRECTION OUTPUT ;
    USE SIGNAL ;
    ANTENNADIFFAREA 0.702900 ;
    PORT
      LAYER met2 ;
        RECT 2770.210 4248.960 2770.490 4249.240 ;
    END
  END gpio_tx_en_o[1]
  PIN gpio_tx_en_o[2]
    DIRECTION OUTPUT ;
    USE SIGNAL ;
    ANTENNADIFFAREA 0.702900 ;
    PORT
      LAYER met2 ;
        RECT 2772.050 4248.960 2772.330 4249.240 ;
    END
  END gpio_tx_en_o[2]
  PIN gpio_tx_en_o[3]
    DIRECTION OUTPUT ;
    USE SIGNAL ;
    ANTENNADIFFAREA 0.702900 ;
    PORT
      LAYER met2 ;
        RECT 2807.010 4248.960 2807.290 4249.240 ;
    END
  END gpio_tx_en_o[3]
  PIN gpio_tx_en_o[4]
    DIRECTION OUTPUT ;
    USE SIGNAL ;
    ANTENNADIFFAREA 0.702900 ;
    PORT
      LAYER met2 ;
        RECT 2766.530 4248.960 2766.810 4249.240 ;
    END
  END gpio_tx_en_o[4]
  PIN gpio_tx_en_o[5]
    DIRECTION OUTPUT ;
    USE SIGNAL ;
    ANTENNADIFFAREA 0.702900 ;
    PORT
      LAYER met2 ;
        RECT 2780.330 4248.960 2780.610 4249.240 ;
    END
  END gpio_tx_en_o[5]
  PIN gpio_tx_en_o[6]
    DIRECTION OUTPUT ;
    USE SIGNAL ;
    ANTENNADIFFAREA 0.702900 ;
    PORT
      LAYER met2 ;
        RECT 2787.690 4248.960 2787.970 4249.240 ;
    END
  END gpio_tx_en_o[6]
  PIN gpio_tx_en_o[7]
    DIRECTION OUTPUT ;
    USE SIGNAL ;
    ANTENNADIFFAREA 0.702900 ;
    PORT
      LAYER met2 ;
        RECT 2801.490 4248.960 2801.770 4249.240 ;
    END
  END gpio_tx_en_o[7]
  PIN gpio_tx_en_o[8]
    DIRECTION OUTPUT ;
    USE SIGNAL ;
    ANTENNADIFFAREA 0.702900 ;
    PORT
      LAYER met2 ;
        RECT 2759.170 4248.960 2759.450 4249.240 ;
    END
  END gpio_tx_en_o[8]
  PIN gpio_tx_en_o[9]
    DIRECTION OUTPUT ;
    USE SIGNAL ;
    ANTENNADIFFAREA 0.702900 ;
    PORT
      LAYER met2 ;
        RECT 2743.530 4248.960 2743.810 4249.240 ;
    END
  END gpio_tx_en_o[9]
  PIN i2c_scl_i
    DIRECTION INPUT ;
    USE SIGNAL ;
    PORT
      LAYER met2 ;
        RECT 1.930 0.000 2.210 0.280 ;
    END
  END i2c_scl_i
  PIN i2c_scl_o
    DIRECTION OUTPUT ;
    USE SIGNAL ;
    PORT
      LAYER met3 ;
        RECT 0.000 760.280 0.600 760.880 ;
    END
  END i2c_scl_o
  PIN i2c_scl_oe
    DIRECTION OUTPUT ;
    USE SIGNAL ;
    ANTENNADIFFAREA 0.702900 ;
    PORT
      LAYER met2 ;
        RECT 2847.490 4248.960 2847.770 4249.240 ;
    END
  END i2c_scl_oe
  PIN i2c_sda_i
    DIRECTION INPUT ;
    USE SIGNAL ;
    ANTENNAGATEAREA 0.159000 ;
    PORT
      LAYER met2 ;
        RECT 2831.850 4248.960 2832.130 4249.240 ;
    END
  END i2c_sda_i
  PIN i2c_sda_o
    DIRECTION OUTPUT ;
    USE SIGNAL ;
    PORT
      LAYER met3 ;
        RECT 0.000 1006.440 0.600 1007.040 ;
    END
  END i2c_sda_o
  PIN i2c_sda_oe
    DIRECTION OUTPUT ;
    USE SIGNAL ;
    ANTENNADIFFAREA 0.702900 ;
    PORT
      LAYER met2 ;
        RECT 2845.650 4248.960 2845.930 4249.240 ;
    END
  END i2c_sda_oe
  PIN jtag_tck
    DIRECTION INPUT ;
    USE SIGNAL ;
    ANTENNAGATEAREA 0.852000 ;
    PORT
      LAYER met3 ;
        RECT 3831.800 3020.600 3832.400 3021.200 ;
    END
  END jtag_tck
  PIN jtag_tdi
    DIRECTION INPUT ;
    USE SIGNAL ;
    ANTENNAGATEAREA 1.177200 ;
    ANTENNADIFFAREA 0.434700 ;
    PORT
      LAYER met3 ;
        RECT 3831.800 3035.560 3832.400 3036.160 ;
    END
  END jtag_tdi
  PIN jtag_tdo
    DIRECTION OUTPUT ;
    USE SIGNAL ;
    ANTENNADIFFAREA 0.702900 ;
    PORT
      LAYER met3 ;
        RECT 3831.800 3042.360 3832.400 3042.960 ;
    END
  END jtag_tdo
  PIN jtag_tms
    DIRECTION INPUT ;
    USE SIGNAL ;
    ANTENNAGATEAREA 0.990000 ;
    PORT
      LAYER met3 ;
        RECT 3831.800 3023.320 3832.400 3023.920 ;
    END
  END jtag_tms
  PIN jtag_trst_n
    DIRECTION INPUT ;
    USE SIGNAL ;
    ANTENNAGATEAREA 0.990000 ;
    PORT
      LAYER met3 ;
        RECT 3831.800 3021.960 3832.400 3022.560 ;
    END
  END jtag_trst_n
  PIN qspi_cs_n
    DIRECTION OUTPUT ;
    USE SIGNAL ;
    ANTENNADIFFAREA 0.702900 ;
    PORT
      LAYER met3 ;
        RECT 0.000 2589.480 0.600 2590.080 ;
    END
  END qspi_cs_n
  PIN qspi_io_i[0]
    DIRECTION INPUT ;
    USE SIGNAL ;
    ANTENNAGATEAREA 0.159000 ;
    PORT
      LAYER met3 ;
        RECT 3831.800 2525.560 3832.400 2526.160 ;
    END
  END qspi_io_i[0]
  PIN qspi_io_i[1]
    DIRECTION INPUT ;
    USE SIGNAL ;
    ANTENNAGATEAREA 0.159000 ;
    PORT
      LAYER met3 ;
        RECT 3831.800 2526.920 3832.400 2527.520 ;
    END
  END qspi_io_i[1]
  PIN qspi_io_i[2]
    DIRECTION INPUT ;
    USE SIGNAL ;
    ANTENNAGATEAREA 0.159000 ;
    PORT
      LAYER met3 ;
        RECT 3831.800 2537.800 3832.400 2538.400 ;
    END
  END qspi_io_i[2]
  PIN qspi_io_i[3]
    DIRECTION INPUT ;
    USE SIGNAL ;
    ANTENNAGATEAREA 0.159000 ;
    PORT
      LAYER met3 ;
        RECT 3831.800 2550.040 3832.400 2550.640 ;
    END
  END qspi_io_i[3]
  PIN qspi_io_o[0]
    DIRECTION OUTPUT ;
    USE SIGNAL ;
    ANTENNADIFFAREA 0.702900 ;
    PORT
      LAYER met3 ;
        RECT 0.000 2558.200 0.600 2558.800 ;
    END
  END qspi_io_o[0]
  PIN qspi_io_o[1]
    DIRECTION OUTPUT ;
    USE SIGNAL ;
    ANTENNADIFFAREA 0.702900 ;
    PORT
      LAYER met3 ;
        RECT 0.000 2575.880 0.600 2576.480 ;
    END
  END qspi_io_o[1]
  PIN qspi_io_o[2]
    DIRECTION OUTPUT ;
    USE SIGNAL ;
    ANTENNADIFFAREA 0.702900 ;
    PORT
      LAYER met3 ;
        RECT 0.000 2560.920 0.600 2561.520 ;
    END
  END qspi_io_o[2]
  PIN qspi_io_o[3]
    DIRECTION OUTPUT ;
    USE SIGNAL ;
    ANTENNADIFFAREA 0.702900 ;
    PORT
      LAYER met3 ;
        RECT 0.000 2559.560 0.600 2560.160 ;
    END
  END qspi_io_o[3]
  PIN qspi_io_oe[0]
    DIRECTION OUTPUT ;
    USE SIGNAL ;
    ANTENNADIFFAREA 0.702900 ;
    PORT
      LAYER met3 ;
        RECT 0.000 2566.360 0.600 2566.960 ;
    END
  END qspi_io_oe[0]
  PIN qspi_io_oe[1]
    DIRECTION OUTPUT ;
    USE SIGNAL ;
    ANTENNADIFFAREA 0.702900 ;
    PORT
      LAYER met3 ;
        RECT 0.000 2563.640 0.600 2564.240 ;
    END
  END qspi_io_oe[1]
  PIN qspi_io_oe[2]
    DIRECTION OUTPUT ;
    USE SIGNAL ;
    ANTENNADIFFAREA 0.702900 ;
    PORT
      LAYER met3 ;
        RECT 0.000 2565.000 0.600 2565.600 ;
    END
  END qspi_io_oe[2]
  PIN qspi_io_oe[3]
    DIRECTION OUTPUT ;
    USE SIGNAL ;
    ANTENNADIFFAREA 0.702900 ;
    PORT
      LAYER met3 ;
        RECT 0.000 2562.280 0.600 2562.880 ;
    END
  END qspi_io_oe[3]
  PIN qspi_sck
    DIRECTION OUTPUT ;
    USE SIGNAL ;
    ANTENNADIFFAREA 0.702900 ;
    PORT
      LAYER met2 ;
        RECT 1652.410 4248.960 1652.690 4249.240 ;
    END
  END qspi_sck
  PIN rst_ni
    DIRECTION INPUT ;
    USE SIGNAL ;
    ANTENNAGATEAREA 0.196500 ;
    PORT
      LAYER met2 ;
        RECT 3062.770 4248.960 3063.050 4249.240 ;
    END
  END rst_ni
  PIN uart1_rxd
    DIRECTION INPUT ;
    USE SIGNAL ;
    ANTENNAGATEAREA 0.213000 ;
    PORT
      LAYER met2 ;
        RECT 2746.290 4248.960 2746.570 4249.240 ;
    END
  END uart1_rxd
  PIN uart1_txd
    DIRECTION OUTPUT ;
    USE SIGNAL ;
    ANTENNADIFFAREA 0.702900 ;
    PORT
      LAYER met2 ;
        RECT 2712.250 4248.960 2712.530 4249.240 ;
    END
  END uart1_txd
  PIN uart2_rxd
    DIRECTION INPUT ;
    USE SIGNAL ;
    ANTENNAGATEAREA 0.213000 ;
    PORT
      LAYER met2 ;
        RECT 1689.210 4248.960 1689.490 4249.240 ;
    END
  END uart2_rxd
  PIN uart2_txd
    DIRECTION OUTPUT ;
    USE SIGNAL ;
    ANTENNADIFFAREA 0.702900 ;
    PORT
      LAYER met2 ;
        RECT 2499.730 4248.960 2500.010 4249.240 ;
    END
  END uart2_txd
  OBS
      LAYER nwell ;
        RECT 5.330 10.795 3826.930 4237.845 ;
      LAYER li1 ;
        RECT 5.520 10.795 3826.740 4237.845 ;
      LAYER met1 ;
        RECT 0.530 10.640 3826.740 4248.260 ;
      LAYER met2 ;
        RECT 0.550 4248.680 1652.130 4249.170 ;
        RECT 1652.970 4248.680 1688.930 4249.170 ;
        RECT 1689.770 4248.680 2499.450 4249.170 ;
        RECT 2500.290 4248.680 2711.970 4249.170 ;
        RECT 2712.810 4248.680 2726.690 4249.170 ;
        RECT 2727.530 4248.680 2727.610 4249.170 ;
        RECT 2728.450 4248.680 2728.530 4249.170 ;
        RECT 2729.370 4248.680 2729.450 4249.170 ;
        RECT 2730.290 4248.680 2730.370 4249.170 ;
        RECT 2731.210 4248.680 2738.650 4249.170 ;
        RECT 2739.490 4248.680 2740.490 4249.170 ;
        RECT 2741.330 4248.680 2741.410 4249.170 ;
        RECT 2742.250 4248.680 2742.330 4249.170 ;
        RECT 2743.170 4248.680 2743.250 4249.170 ;
        RECT 2744.090 4248.680 2745.090 4249.170 ;
        RECT 2745.930 4248.680 2746.010 4249.170 ;
        RECT 2746.850 4248.680 2746.930 4249.170 ;
        RECT 2747.770 4248.680 2747.850 4249.170 ;
        RECT 2748.690 4248.680 2751.530 4249.170 ;
        RECT 2752.370 4248.680 2752.450 4249.170 ;
        RECT 2753.290 4248.680 2757.970 4249.170 ;
        RECT 2758.810 4248.680 2758.890 4249.170 ;
        RECT 2759.730 4248.680 2766.250 4249.170 ;
        RECT 2767.090 4248.680 2767.170 4249.170 ;
        RECT 2768.010 4248.680 2768.090 4249.170 ;
        RECT 2768.930 4248.680 2769.010 4249.170 ;
        RECT 2769.850 4248.680 2769.930 4249.170 ;
        RECT 2770.770 4248.680 2771.770 4249.170 ;
        RECT 2772.610 4248.680 2777.290 4249.170 ;
        RECT 2778.130 4248.680 2780.050 4249.170 ;
        RECT 2780.890 4248.680 2780.970 4249.170 ;
        RECT 2781.810 4248.680 2781.890 4249.170 ;
        RECT 2782.730 4248.680 2782.810 4249.170 ;
        RECT 2783.650 4248.680 2783.730 4249.170 ;
        RECT 2784.570 4248.680 2786.490 4249.170 ;
        RECT 2787.330 4248.680 2787.410 4249.170 ;
        RECT 2788.250 4248.680 2797.530 4249.170 ;
        RECT 2798.370 4248.680 2801.210 4249.170 ;
        RECT 2802.050 4248.680 2802.130 4249.170 ;
        RECT 2802.970 4248.680 2803.050 4249.170 ;
        RECT 2803.890 4248.680 2803.970 4249.170 ;
        RECT 2804.810 4248.680 2804.890 4249.170 ;
        RECT 2805.730 4248.680 2805.810 4249.170 ;
        RECT 2806.650 4248.680 2806.730 4249.170 ;
        RECT 2807.570 4248.680 2807.650 4249.170 ;
        RECT 2808.490 4248.680 2808.570 4249.170 ;
        RECT 2809.410 4248.680 2809.490 4249.170 ;
        RECT 2810.330 4248.680 2820.530 4249.170 ;
        RECT 2821.370 4248.680 2827.890 4249.170 ;
        RECT 2828.730 4248.680 2831.570 4249.170 ;
        RECT 2832.410 4248.680 2832.490 4249.170 ;
        RECT 2833.330 4248.680 2833.410 4249.170 ;
        RECT 2834.250 4248.680 2841.690 4249.170 ;
        RECT 2842.530 4248.680 2842.610 4249.170 ;
        RECT 2843.450 4248.680 2845.370 4249.170 ;
        RECT 2846.210 4248.680 2847.210 4249.170 ;
        RECT 2848.050 4248.680 3062.490 4249.170 ;
        RECT 3063.330 4248.680 3825.270 4249.170 ;
        RECT 0.550 10.695 3825.270 4248.680 ;
      LAYER met3 ;
        RECT 0.600 3974.960 3831.800 4237.925 ;
        RECT 1.000 3973.560 3831.800 3974.960 ;
        RECT 0.600 3043.360 3831.800 3973.560 ;
        RECT 0.600 3041.960 3831.400 3043.360 ;
        RECT 0.600 3036.560 3831.800 3041.960 ;
        RECT 0.600 3035.160 3831.400 3036.560 ;
        RECT 0.600 3024.320 3831.800 3035.160 ;
        RECT 0.600 3020.200 3831.400 3024.320 ;
        RECT 0.600 2590.480 3831.800 3020.200 ;
        RECT 1.000 2589.080 3831.800 2590.480 ;
        RECT 0.600 2576.880 3831.800 2589.080 ;
        RECT 1.000 2575.480 3831.800 2576.880 ;
        RECT 0.600 2567.360 3831.800 2575.480 ;
        RECT 1.000 2557.800 3831.800 2567.360 ;
        RECT 0.600 2551.040 3831.800 2557.800 ;
        RECT 0.600 2549.640 3831.400 2551.040 ;
        RECT 0.600 2538.800 3831.800 2549.640 ;
        RECT 0.600 2537.400 3831.400 2538.800 ;
        RECT 0.600 2527.920 3831.800 2537.400 ;
        RECT 0.600 2525.160 3831.400 2527.920 ;
        RECT 0.600 1007.440 3831.800 2525.160 ;
        RECT 1.000 1006.040 3831.800 1007.440 ;
        RECT 0.600 761.280 3831.800 1006.040 ;
        RECT 1.000 759.880 3831.800 761.280 ;
        RECT 0.600 10.715 3831.800 759.880 ;
      LAYER met4 ;
        RECT 231.710 3778.520 327.840 4230.785 ;
        RECT 330.240 3778.520 331.140 4230.785 ;
        RECT 333.540 3778.520 481.440 4230.785 ;
        RECT 483.840 3778.520 484.740 4230.785 ;
        RECT 487.140 3778.520 635.040 4230.785 ;
        RECT 637.440 3778.520 638.340 4230.785 ;
        RECT 640.740 3778.520 788.640 4230.785 ;
        RECT 791.040 3778.520 791.940 4230.785 ;
        RECT 794.340 3778.520 942.240 4230.785 ;
        RECT 944.640 3778.520 945.540 4230.785 ;
        RECT 947.940 3778.520 1095.840 4230.785 ;
        RECT 231.710 3303.420 1095.840 3778.520 ;
        RECT 231.710 3302.500 331.140 3303.420 ;
        RECT 231.710 3161.980 327.840 3302.500 ;
        RECT 330.240 3161.980 331.140 3302.500 ;
        RECT 333.540 3302.500 484.740 3303.420 ;
        RECT 333.540 3161.980 481.440 3302.500 ;
        RECT 483.840 3161.980 484.740 3302.500 ;
        RECT 487.140 3161.980 635.040 3303.420 ;
        RECT 637.440 3161.980 638.340 3303.420 ;
        RECT 640.740 3161.980 788.640 3303.420 ;
        RECT 791.040 3161.980 791.940 3303.420 ;
        RECT 794.340 3161.980 942.240 3303.420 ;
        RECT 944.640 3161.980 945.540 3303.420 ;
        RECT 947.940 3161.980 1095.840 3303.420 ;
        RECT 231.710 2686.880 1095.840 3161.980 ;
        RECT 231.710 2685.960 331.140 2686.880 ;
        RECT 231.710 2545.440 327.840 2685.960 ;
        RECT 330.240 2545.440 331.140 2685.960 ;
        RECT 333.540 2685.960 484.740 2686.880 ;
        RECT 333.540 2545.440 481.440 2685.960 ;
        RECT 483.840 2545.440 484.740 2685.960 ;
        RECT 487.140 2545.440 635.040 2686.880 ;
        RECT 637.440 2545.440 638.340 2686.880 ;
        RECT 640.740 2545.440 788.640 2686.880 ;
        RECT 791.040 2545.440 791.940 2686.880 ;
        RECT 794.340 2545.440 942.240 2686.880 ;
        RECT 944.640 2545.440 945.540 2686.880 ;
        RECT 947.940 2545.440 1095.840 2686.880 ;
        RECT 231.710 2070.340 1095.840 2545.440 ;
        RECT 231.710 2069.420 331.140 2070.340 ;
        RECT 231.710 1928.900 327.840 2069.420 ;
        RECT 330.240 1928.900 331.140 2069.420 ;
        RECT 333.540 2069.420 484.740 2070.340 ;
        RECT 333.540 1928.900 481.440 2069.420 ;
        RECT 483.840 1928.900 484.740 2069.420 ;
        RECT 487.140 1928.900 635.040 2070.340 ;
        RECT 637.440 1928.900 638.340 2070.340 ;
        RECT 640.740 1928.900 788.640 2070.340 ;
        RECT 791.040 1928.900 791.940 2070.340 ;
        RECT 794.340 1928.900 942.240 2070.340 ;
        RECT 944.640 1928.900 945.540 2070.340 ;
        RECT 947.940 1928.900 1095.840 2070.340 ;
        RECT 231.710 1453.800 1095.840 1928.900 ;
        RECT 231.710 1452.880 331.140 1453.800 ;
        RECT 231.710 1312.360 327.840 1452.880 ;
        RECT 330.240 1312.360 331.140 1452.880 ;
        RECT 333.540 1452.880 484.740 1453.800 ;
        RECT 333.540 1312.360 481.440 1452.880 ;
        RECT 483.840 1312.360 484.740 1452.880 ;
        RECT 487.140 1312.360 635.040 1453.800 ;
        RECT 637.440 1312.360 638.340 1453.800 ;
        RECT 640.740 1312.360 788.640 1453.800 ;
        RECT 791.040 1312.360 791.940 1453.800 ;
        RECT 794.340 1312.360 942.240 1453.800 ;
        RECT 944.640 1312.360 945.540 1453.800 ;
        RECT 947.940 1312.360 1095.840 1453.800 ;
        RECT 231.710 837.260 1095.840 1312.360 ;
        RECT 231.710 836.340 331.140 837.260 ;
        RECT 231.710 695.820 327.840 836.340 ;
        RECT 330.240 695.820 331.140 836.340 ;
        RECT 333.540 836.340 484.740 837.260 ;
        RECT 333.540 695.820 481.440 836.340 ;
        RECT 483.840 695.820 484.740 836.340 ;
        RECT 487.140 695.820 635.040 837.260 ;
        RECT 637.440 695.820 638.340 837.260 ;
        RECT 640.740 695.820 788.640 837.260 ;
        RECT 791.040 695.820 791.940 837.260 ;
        RECT 794.340 695.820 942.240 837.260 ;
        RECT 944.640 695.820 945.540 837.260 ;
        RECT 947.940 695.820 1095.840 837.260 ;
        RECT 231.710 220.720 1095.840 695.820 ;
        RECT 231.710 219.800 331.140 220.720 ;
        RECT 231.710 189.895 327.840 219.800 ;
        RECT 330.240 189.895 331.140 219.800 ;
        RECT 333.540 219.800 484.740 220.720 ;
        RECT 333.540 189.895 481.440 219.800 ;
        RECT 483.840 189.895 484.740 219.800 ;
        RECT 487.140 189.895 635.040 220.720 ;
        RECT 637.440 189.895 638.340 220.720 ;
        RECT 640.740 189.895 788.640 220.720 ;
        RECT 791.040 189.895 791.940 220.720 ;
        RECT 794.340 189.895 942.240 220.720 ;
        RECT 944.640 189.895 945.540 220.720 ;
        RECT 947.940 189.895 1095.840 220.720 ;
        RECT 1098.240 189.895 1099.140 4230.785 ;
        RECT 1101.540 3778.520 1249.440 4230.785 ;
        RECT 1251.840 3778.520 1252.740 4230.785 ;
        RECT 1255.140 3778.520 1403.040 4230.785 ;
        RECT 1405.440 3778.520 1406.340 4230.785 ;
        RECT 1408.740 3778.520 1556.640 4230.785 ;
        RECT 1559.040 3778.520 1559.940 4230.785 ;
        RECT 1562.340 3778.520 1710.240 4230.785 ;
        RECT 1712.640 3778.520 1713.540 4230.785 ;
        RECT 1715.940 3778.520 1863.840 4230.785 ;
        RECT 1101.540 3303.420 1863.840 3778.520 ;
        RECT 1101.540 3161.980 1249.440 3303.420 ;
        RECT 1251.840 3302.720 1406.340 3303.420 ;
        RECT 1251.840 3161.980 1252.740 3302.720 ;
        RECT 1255.140 3302.500 1406.340 3302.720 ;
        RECT 1255.140 3161.980 1403.040 3302.500 ;
        RECT 1405.440 3161.980 1406.340 3302.500 ;
        RECT 1408.740 3161.980 1556.640 3303.420 ;
        RECT 1559.040 3161.980 1559.940 3303.420 ;
        RECT 1562.340 3161.980 1710.240 3303.420 ;
        RECT 1712.640 3161.980 1713.540 3303.420 ;
        RECT 1715.940 3161.980 1863.840 3303.420 ;
        RECT 1101.540 2686.880 1863.840 3161.980 ;
        RECT 1101.540 2545.440 1249.440 2686.880 ;
        RECT 1251.840 2685.960 1406.340 2686.880 ;
        RECT 1251.840 2545.440 1252.740 2685.960 ;
        RECT 1255.140 2545.440 1403.040 2685.960 ;
        RECT 1405.440 2545.440 1406.340 2685.960 ;
        RECT 1408.740 2545.440 1556.640 2686.880 ;
        RECT 1559.040 2545.440 1559.940 2686.880 ;
        RECT 1562.340 2545.440 1710.240 2686.880 ;
        RECT 1712.640 2545.440 1713.540 2686.880 ;
        RECT 1715.940 2545.440 1863.840 2686.880 ;
        RECT 1101.540 2070.340 1863.840 2545.440 ;
        RECT 1101.540 1928.900 1249.440 2070.340 ;
        RECT 1251.840 2069.420 1406.340 2070.340 ;
        RECT 1251.840 1928.900 1252.740 2069.420 ;
        RECT 1255.140 1928.900 1403.040 2069.420 ;
        RECT 1405.440 1928.900 1406.340 2069.420 ;
        RECT 1408.740 1928.900 1556.640 2070.340 ;
        RECT 1559.040 1928.900 1559.940 2070.340 ;
        RECT 1562.340 1928.900 1710.240 2070.340 ;
        RECT 1712.640 1928.900 1713.540 2070.340 ;
        RECT 1715.940 1928.900 1863.840 2070.340 ;
        RECT 1101.540 1453.800 1863.840 1928.900 ;
        RECT 1101.540 1312.360 1249.440 1453.800 ;
        RECT 1251.840 1453.120 1406.340 1453.800 ;
        RECT 1251.840 1312.360 1252.740 1453.120 ;
        RECT 1255.140 1452.880 1406.340 1453.120 ;
        RECT 1255.140 1312.360 1403.040 1452.880 ;
        RECT 1405.440 1312.360 1406.340 1452.880 ;
        RECT 1408.740 1312.360 1556.640 1453.800 ;
        RECT 1559.040 1312.360 1559.940 1453.800 ;
        RECT 1562.340 1312.360 1710.240 1453.800 ;
        RECT 1712.640 1312.360 1713.540 1453.800 ;
        RECT 1715.940 1312.360 1863.840 1453.800 ;
        RECT 1101.540 837.260 1863.840 1312.360 ;
        RECT 1101.540 695.820 1249.440 837.260 ;
        RECT 1251.840 836.340 1406.340 837.260 ;
        RECT 1251.840 695.820 1252.740 836.340 ;
        RECT 1255.140 695.820 1403.040 836.340 ;
        RECT 1405.440 695.820 1406.340 836.340 ;
        RECT 1408.740 695.820 1556.640 837.260 ;
        RECT 1559.040 695.820 1559.940 837.260 ;
        RECT 1562.340 695.820 1710.240 837.260 ;
        RECT 1712.640 695.820 1713.540 837.260 ;
        RECT 1715.940 695.820 1863.840 837.260 ;
        RECT 1101.540 220.720 1863.840 695.820 ;
        RECT 1101.540 189.895 1249.440 220.720 ;
        RECT 1251.840 219.800 1406.340 220.720 ;
        RECT 1251.840 189.895 1252.740 219.800 ;
        RECT 1255.140 189.895 1403.040 219.800 ;
        RECT 1405.440 189.895 1406.340 219.800 ;
        RECT 1408.740 189.895 1556.640 220.720 ;
        RECT 1559.040 189.895 1559.940 220.720 ;
        RECT 1562.340 189.895 1710.240 220.720 ;
        RECT 1712.640 189.895 1713.540 220.720 ;
        RECT 1715.940 189.895 1863.840 220.720 ;
        RECT 1866.240 189.895 1867.140 4230.785 ;
        RECT 1869.540 3778.520 2017.440 4230.785 ;
        RECT 2019.840 3778.520 2020.740 4230.785 ;
        RECT 2023.140 3779.440 2171.040 4230.785 ;
        RECT 2173.440 3779.440 2174.340 4230.785 ;
        RECT 2023.140 3778.520 2174.340 3779.440 ;
        RECT 2176.740 3778.520 2324.640 4230.785 ;
        RECT 2327.040 3778.520 2327.940 4230.785 ;
        RECT 2330.340 3778.520 2478.240 4230.785 ;
        RECT 2480.640 3779.440 2481.540 4230.785 ;
        RECT 2483.940 3779.440 2631.840 4230.785 ;
        RECT 2480.640 3778.520 2631.840 3779.440 ;
        RECT 2634.240 3778.520 2635.140 4230.785 ;
        RECT 2637.540 3778.520 2785.440 4230.785 ;
        RECT 1869.540 3303.420 2785.440 3778.520 ;
        RECT 1869.540 3161.980 2017.440 3303.420 ;
        RECT 2019.840 3161.980 2020.740 3303.420 ;
        RECT 2023.140 3302.500 2174.340 3303.420 ;
        RECT 2023.140 3162.720 2171.040 3302.500 ;
        RECT 2173.440 3162.720 2174.340 3302.500 ;
        RECT 2023.140 3161.980 2174.340 3162.720 ;
        RECT 2176.740 3161.980 2324.640 3303.420 ;
        RECT 2327.040 3161.980 2327.940 3303.420 ;
        RECT 2330.340 3161.980 2478.240 3303.420 ;
        RECT 2480.640 3302.720 2635.140 3303.420 ;
        RECT 2480.640 3162.900 2481.540 3302.720 ;
        RECT 2483.940 3302.500 2635.140 3302.720 ;
        RECT 2483.940 3162.900 2631.840 3302.500 ;
        RECT 2480.640 3161.980 2631.840 3162.900 ;
        RECT 2634.240 3161.980 2635.140 3302.500 ;
        RECT 2637.540 3161.980 2785.440 3303.420 ;
        RECT 1869.540 2686.880 2785.440 3161.980 ;
        RECT 1869.540 2545.440 2017.440 2686.880 ;
        RECT 2019.840 2545.440 2020.740 2686.880 ;
        RECT 2023.140 2685.960 2174.340 2686.880 ;
        RECT 2023.140 2546.360 2171.040 2685.960 ;
        RECT 2173.440 2546.360 2174.340 2685.960 ;
        RECT 2023.140 2545.440 2174.340 2546.360 ;
        RECT 2176.740 2545.440 2324.640 2686.880 ;
        RECT 2327.040 2545.440 2327.940 2686.880 ;
        RECT 2330.340 2545.440 2478.240 2686.880 ;
        RECT 2480.640 2685.960 2635.140 2686.880 ;
        RECT 2480.640 2546.360 2481.540 2685.960 ;
        RECT 2483.940 2546.360 2631.840 2685.960 ;
        RECT 2480.640 2545.440 2631.840 2546.360 ;
        RECT 2634.240 2545.440 2635.140 2685.960 ;
        RECT 2637.540 2545.440 2785.440 2686.880 ;
        RECT 1869.540 2070.340 2785.440 2545.440 ;
        RECT 1869.540 1928.900 2017.440 2070.340 ;
        RECT 2019.840 1928.900 2020.740 2070.340 ;
        RECT 2023.140 2069.420 2174.340 2070.340 ;
        RECT 2023.140 1929.820 2171.040 2069.420 ;
        RECT 2173.440 1929.820 2174.340 2069.420 ;
        RECT 2023.140 1928.900 2174.340 1929.820 ;
        RECT 2176.740 1928.900 2324.640 2070.340 ;
        RECT 2327.040 1928.900 2327.940 2070.340 ;
        RECT 2330.340 1928.900 2478.240 2070.340 ;
        RECT 2480.640 2069.420 2635.140 2070.340 ;
        RECT 2480.640 1929.820 2481.540 2069.420 ;
        RECT 2483.940 1929.820 2631.840 2069.420 ;
        RECT 2480.640 1928.900 2631.840 1929.820 ;
        RECT 2634.240 1928.900 2635.140 2069.420 ;
        RECT 2637.540 1928.900 2785.440 2070.340 ;
        RECT 1869.540 1453.800 2785.440 1928.900 ;
        RECT 1869.540 1312.360 2017.440 1453.800 ;
        RECT 2019.840 1312.360 2020.740 1453.800 ;
        RECT 2023.140 1452.880 2174.340 1453.800 ;
        RECT 2023.140 1313.120 2171.040 1452.880 ;
        RECT 2173.440 1313.120 2174.340 1452.880 ;
        RECT 2023.140 1312.360 2174.340 1313.120 ;
        RECT 2176.740 1312.360 2324.640 1453.800 ;
        RECT 2327.040 1312.360 2327.940 1453.800 ;
        RECT 2330.340 1312.360 2478.240 1453.800 ;
        RECT 2480.640 1453.120 2635.140 1453.800 ;
        RECT 2480.640 1313.280 2481.540 1453.120 ;
        RECT 2483.940 1452.880 2635.140 1453.120 ;
        RECT 2483.940 1313.280 2631.840 1452.880 ;
        RECT 2480.640 1312.360 2631.840 1313.280 ;
        RECT 2634.240 1312.360 2635.140 1452.880 ;
        RECT 2637.540 1312.360 2785.440 1453.800 ;
        RECT 1869.540 837.260 2785.440 1312.360 ;
        RECT 1869.540 695.820 2017.440 837.260 ;
        RECT 2019.840 695.820 2020.740 837.260 ;
        RECT 2023.140 836.340 2174.340 837.260 ;
        RECT 2023.140 696.740 2171.040 836.340 ;
        RECT 2173.440 696.740 2174.340 836.340 ;
        RECT 2023.140 695.820 2174.340 696.740 ;
        RECT 2176.740 695.820 2324.640 837.260 ;
        RECT 2327.040 695.820 2327.940 837.260 ;
        RECT 2330.340 695.820 2478.240 837.260 ;
        RECT 2480.640 836.340 2635.140 837.260 ;
        RECT 2480.640 696.740 2481.540 836.340 ;
        RECT 2483.940 696.740 2631.840 836.340 ;
        RECT 2480.640 695.820 2631.840 696.740 ;
        RECT 2634.240 695.820 2635.140 836.340 ;
        RECT 2637.540 695.820 2785.440 837.260 ;
        RECT 1869.540 220.720 2785.440 695.820 ;
        RECT 1869.540 189.895 2017.440 220.720 ;
        RECT 2019.840 189.895 2020.740 220.720 ;
        RECT 2023.140 219.800 2174.340 220.720 ;
        RECT 2023.140 189.895 2171.040 219.800 ;
        RECT 2173.440 189.895 2174.340 219.800 ;
        RECT 2176.740 189.895 2324.640 220.720 ;
        RECT 2327.040 189.895 2327.940 220.720 ;
        RECT 2330.340 189.895 2478.240 220.720 ;
        RECT 2480.640 219.800 2635.140 220.720 ;
        RECT 2480.640 189.895 2481.540 219.800 ;
        RECT 2483.940 189.895 2631.840 219.800 ;
        RECT 2634.240 189.895 2635.140 219.800 ;
        RECT 2637.540 189.895 2785.440 220.720 ;
        RECT 2787.840 189.895 2788.740 4230.785 ;
        RECT 2791.140 3778.520 2939.040 4230.785 ;
        RECT 2941.440 3778.520 2942.340 4230.785 ;
        RECT 2944.740 3778.520 3092.640 4230.785 ;
        RECT 3095.040 3778.520 3095.940 4230.785 ;
        RECT 3098.340 3778.520 3246.240 4230.785 ;
        RECT 3248.640 3778.520 3249.540 4230.785 ;
        RECT 3251.940 3778.520 3399.840 4230.785 ;
        RECT 3402.240 3779.440 3403.140 4230.785 ;
        RECT 3405.540 3779.440 3553.440 4230.785 ;
        RECT 3555.840 3779.440 3556.740 4230.785 ;
        RECT 3402.240 3778.520 3556.740 3779.440 ;
        RECT 3559.140 3778.520 3581.040 4230.785 ;
        RECT 2791.140 3303.420 3581.040 3778.520 ;
        RECT 2791.140 3161.980 2939.040 3303.420 ;
        RECT 2941.440 3161.980 2942.340 3303.420 ;
        RECT 2944.740 3161.980 3092.640 3303.420 ;
        RECT 3095.040 3302.720 3246.240 3303.420 ;
        RECT 3095.040 3161.980 3095.940 3302.720 ;
        RECT 3098.340 3161.980 3246.240 3302.720 ;
        RECT 3248.640 3161.980 3249.540 3303.420 ;
        RECT 3251.940 3161.980 3399.840 3303.420 ;
        RECT 3402.240 3302.720 3553.440 3303.420 ;
        RECT 3402.240 3162.900 3403.140 3302.720 ;
        RECT 3405.540 3162.900 3553.440 3302.720 ;
        RECT 3402.240 3162.720 3553.440 3162.900 ;
        RECT 3555.840 3162.720 3556.740 3303.420 ;
        RECT 3402.240 3161.980 3556.740 3162.720 ;
        RECT 3559.140 3161.980 3581.040 3303.420 ;
        RECT 2791.140 2686.880 3581.040 3161.980 ;
        RECT 2791.140 1928.900 2939.040 2686.880 ;
        RECT 2941.440 1928.900 2942.340 2686.880 ;
        RECT 2944.740 1928.900 3092.640 2686.880 ;
        RECT 3095.040 2685.960 3246.240 2686.880 ;
        RECT 3095.040 1928.900 3095.940 2685.960 ;
        RECT 3098.340 1928.900 3246.240 2685.960 ;
        RECT 3248.640 1928.900 3249.540 2686.880 ;
        RECT 3251.940 1928.900 3399.840 2686.880 ;
        RECT 3402.240 2685.960 3553.440 2686.880 ;
        RECT 3402.240 1929.820 3403.140 2685.960 ;
        RECT 3405.540 1929.820 3553.440 2685.960 ;
        RECT 3555.840 1929.820 3556.740 2686.880 ;
        RECT 3402.240 1928.900 3556.740 1929.820 ;
        RECT 3559.140 1928.900 3581.040 2686.880 ;
        RECT 2791.140 1453.800 3581.040 1928.900 ;
        RECT 2791.140 1312.360 2939.040 1453.800 ;
        RECT 2941.440 1312.360 2942.340 1453.800 ;
        RECT 2944.740 1312.360 3092.640 1453.800 ;
        RECT 3095.040 1453.120 3246.240 1453.800 ;
        RECT 3095.040 1312.360 3095.940 1453.120 ;
        RECT 3098.340 1312.360 3246.240 1453.120 ;
        RECT 3248.640 1312.360 3249.540 1453.800 ;
        RECT 3251.940 1312.360 3399.840 1453.800 ;
        RECT 3402.240 1453.120 3553.440 1453.800 ;
        RECT 3402.240 1313.280 3403.140 1453.120 ;
        RECT 3405.540 1313.280 3553.440 1453.120 ;
        RECT 3402.240 1313.120 3553.440 1313.280 ;
        RECT 3555.840 1313.120 3556.740 1453.800 ;
        RECT 3402.240 1312.360 3556.740 1313.120 ;
        RECT 3559.140 1312.360 3581.040 1453.800 ;
        RECT 2791.140 837.260 3581.040 1312.360 ;
        RECT 2791.140 695.820 2939.040 837.260 ;
        RECT 2941.440 695.820 2942.340 837.260 ;
        RECT 2944.740 695.820 3092.640 837.260 ;
        RECT 3095.040 836.340 3246.240 837.260 ;
        RECT 3095.040 695.820 3095.940 836.340 ;
        RECT 3098.340 695.820 3246.240 836.340 ;
        RECT 3248.640 695.820 3249.540 837.260 ;
        RECT 3251.940 695.820 3399.840 837.260 ;
        RECT 3402.240 836.340 3553.440 837.260 ;
        RECT 3402.240 696.740 3403.140 836.340 ;
        RECT 3405.540 696.740 3553.440 836.340 ;
        RECT 3555.840 696.740 3556.740 837.260 ;
        RECT 3402.240 695.820 3556.740 696.740 ;
        RECT 3559.140 695.820 3581.040 837.260 ;
        RECT 2791.140 220.720 3581.040 695.820 ;
        RECT 2791.140 189.895 2939.040 220.720 ;
        RECT 2941.440 189.895 2942.340 220.720 ;
        RECT 2944.740 189.895 3092.640 220.720 ;
        RECT 3095.040 219.800 3246.240 220.720 ;
        RECT 3095.040 189.895 3095.940 219.800 ;
        RECT 3098.340 189.895 3246.240 219.800 ;
        RECT 3248.640 189.895 3249.540 220.720 ;
        RECT 3251.940 189.895 3399.840 220.720 ;
        RECT 3402.240 219.800 3553.440 220.720 ;
        RECT 3402.240 189.895 3403.140 219.800 ;
        RECT 3405.540 189.895 3553.440 219.800 ;
        RECT 3555.840 189.895 3556.740 220.720 ;
        RECT 3559.140 189.895 3581.040 220.720 ;
      LAYER met5 ;
        RECT 231.500 4169.090 3550.620 4228.700 ;
        RECT 231.500 4015.910 3550.620 4160.990 ;
        RECT 231.500 3862.730 3550.620 4007.810 ;
        RECT 231.500 3709.550 3550.620 3854.630 ;
        RECT 231.500 3556.370 3550.620 3701.450 ;
        RECT 231.500 3403.190 3550.620 3548.270 ;
        RECT 231.500 3250.010 3550.620 3395.090 ;
        RECT 231.500 3096.830 3550.620 3241.910 ;
        RECT 231.500 2943.650 3550.620 3088.730 ;
        RECT 231.500 2790.470 3550.620 2935.550 ;
        RECT 231.500 2637.290 3550.620 2782.370 ;
        RECT 231.500 2484.110 3550.620 2629.190 ;
        RECT 231.500 2330.930 3550.620 2476.010 ;
        RECT 231.500 2177.750 3550.620 2322.830 ;
        RECT 231.500 2024.570 3550.620 2169.650 ;
        RECT 231.500 1871.390 3550.620 2016.470 ;
        RECT 231.500 1718.210 3550.620 1863.290 ;
        RECT 231.500 1565.030 3550.620 1710.110 ;
        RECT 231.500 1411.850 3550.620 1556.930 ;
        RECT 231.500 1258.670 3550.620 1403.750 ;
        RECT 231.500 1105.490 3550.620 1250.570 ;
        RECT 231.500 952.310 3550.620 1097.390 ;
        RECT 231.500 799.130 3550.620 944.210 ;
        RECT 231.500 645.950 3550.620 791.030 ;
        RECT 231.500 492.770 3550.620 637.850 ;
        RECT 231.500 339.590 3550.620 484.670 ;
        RECT 231.500 238.900 3550.620 331.490 ;
  END
END soc_top
END LIBRARY

